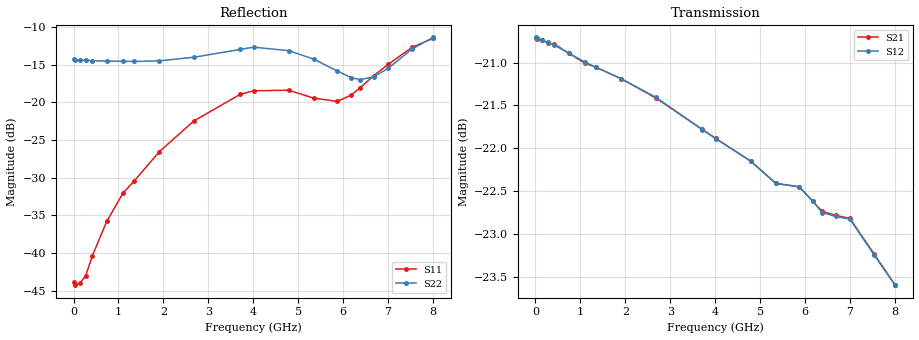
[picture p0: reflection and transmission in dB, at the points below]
! DEVICE ID: PE43712
! File Path: z:\PE43713\PE43713_CHAR_NOM_04292014\AMB\3p300\LS_ATT_19p50dB\PE43713_AMB_3p300V_3p000V_0p000V_LS_ATT_19p50dB_S2P_SN_10_A0139A.s2p
! Serial: 10
! Lot: A0139A
! Temp: 25C
! VDD: 3.300
! VSS: 0.000
! Control_Hi: 3.000
! Control_Lo: 0.000
! Attenuation Step: 19.50dB
! Port 1: RF1
! Port 2: RF2
! ThroughPath:1-2
! IDD: 0.000146803
! ISS: -1.27e-007
#  Hz  S  RI  R  50
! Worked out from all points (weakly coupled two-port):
!   801 points, 10 MHz to 8.01 GHz, reference 50 ohm
!   highest |S21| = -20.72 dB at 10 MHz (marker M1); lowest = -23.6 dB at 8 GHz (marker M2)
!   lowest |S11| = -44.2 dB at 40 MHz (marker M3), VSWR 1.01, Z = 49.4 + j0.17 ohm
!   |S11| at or under -10 dB: start of sweep to end of sweep
!   |S22| runs from -17.0 to -11.4 dB; largest |S21 - S12| = 0.00033
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1e7  -0.00638 0.000578  0.0921 -0.000419  0.0922 -0.000446  -0.1932 0.00121
4e7  -0.00589 0.00172  0.092 -0.00154  0.0921 -0.00153  -0.1924 0.00401
1.5e8  -0.00516 0.00373  0.0917 -0.00538  0.0917 -0.00538  -0.191 0.0115
2.7e8  -0.00447 0.00548  0.091 -0.00943  0.0911 -0.00948  -0.1893 0.0184
4.2e8  -0.00413 0.00869  0.0902 -0.0145  0.0901 -0.0145  -0.1873 0.0272
7.4e8  -0.00379 0.0158  0.0869 -0.0244  0.0869 -0.0244  -0.1821 0.0476
1.1e9  -0.0024 0.0249  0.0821 -0.0345  0.0822 -0.0346  -0.1744 0.0692
1.35e9  3.59e-05 0.0301  0.0785 -0.041  0.0785 -0.041  -0.1681 0.0823
1.91e9  0.00876 0.0463  0.0684 -0.0541  0.0684 -0.0541  -0.1487 0.1164
2.68e9  0.0268 0.0705  0.0511 -0.0679  0.0511 -0.068  -0.1152 0.163
3.71e9  0.039 0.1062  0.0242 -0.0778  0.0241 -0.0778  -0.0859 0.2077
4.01e9  0.0402 0.1126  0.0164 -0.0788  0.0163 -0.0788  -0.0838 0.2171
4.79e9  0.0438 0.1123  -0.00316 -0.078  -0.00316 -0.078  -0.0667 0.2103
5.35e9  0.0562 0.0908  -0.0158 -0.0741  -0.0158 -0.0741  -0.0481 0.1876
5.87e9  0.0769 0.0665  -0.0273 -0.0703  -0.0273 -0.0703  -0.00826 0.1617
6.17e9  0.0952 0.0579  -0.0342 -0.0656  -0.034 -0.0657  0.023 0.1446
6.38e9  0.1122 0.0555  -0.0373 -0.0627  -0.0371 -0.0627  0.0484 0.1332
6.68e9  0.1412 0.052  -0.0427 -0.0587  -0.0425 -0.0587  0.0867 0.1198
7e9  0.1705 0.0535  -0.0487 -0.0534  -0.0486 -0.0534  0.1228 0.1149
7.54e9  0.2242 0.062  -0.0552 -0.0412  -0.0551 -0.0412  0.1903 0.1237
8e9  0.2549 0.0756  -0.0577 -0.0323  -0.0576 -0.0324  0.2335 0.1349
8.01e9  0.2554 0.0763  -0.0577 -0.0322  -0.0576 -0.0324  0.2342 0.1349
